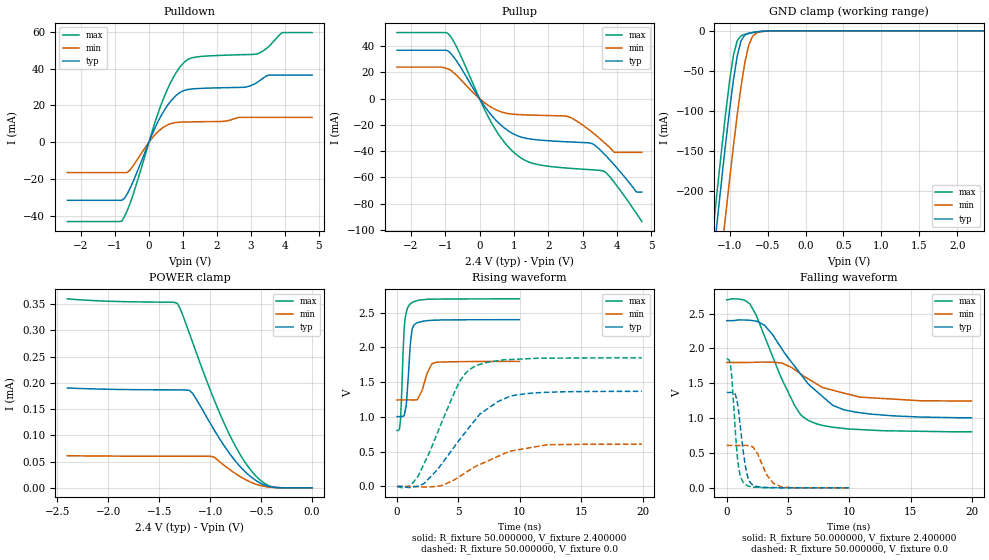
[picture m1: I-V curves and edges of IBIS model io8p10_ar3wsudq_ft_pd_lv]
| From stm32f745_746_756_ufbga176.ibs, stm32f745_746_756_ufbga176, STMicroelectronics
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|   Model io8p10_ar3wsudq_ft_pd_lv
[Model]  io8p10_ar3wsudq_ft_pd_lv
Model_type I/O
Polarity   Non-Inverting
Enable   Active-Low
Vinl =   0.720000V
Vinh =   1.680000V
Vmeas =  1.200000V
Cref =   40.000000pF
Rref =   100.000000M
Vref =   0.0V
C_comp   3.720900pF   3.684200pF   3.822900pF
[Temperature Range]   25.000000   0.125000k   -40.000000
[Pullup Reference]   2.400000V   1.800000V   2.700000V
[Pulldown Reference]   0.0V   0.0V   0.0V
[POWER Clamp Reference]   2.400000V   1.800000V   2.700000V
[GND Clamp Reference]   0.0V   0.0V   0.0V
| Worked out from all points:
|   slope of the pulldown table from 0 to 0.36 V, typ, clamps not added: 25 ohm
|   slope of the pullup table from 0 to 0.36 V, typ, clamps not added: 27.7 ohm
|   GND clamp passes 1 mA (typ) near -0.62 V on its own axis
|   rising waveform, R_fixture 50.000000, V_fixture 2.400000: 20-80 % time 334ps typ, 653ps min, 263ps max; typ from 1 V to 2.4 V
|   rising waveform, R_fixture 50.000000, V_fixture 0.0: 20-80 % time 3.76ns typ, 4ns min, 2.7ns max; typ from 0 V to 1.37 V
|   falling waveform, R_fixture 50.000000, V_fixture 2.400000: 20-80 % time 3.96ns typ, 4.04ns min, 2.77ns max; typ from 2.4 V to 1 V
|   falling waveform, R_fixture 50.000000, V_fixture 0.0: 20-80 % time 590ps typ, 1.03ns min, 462ps max; typ from 1.37 V to 0 V
[Pulldown]
|Voltage   I(typ)   I(min)   I(max)
-2.4V     -31.47mA   -16.45mA   -43.01mA
-800mV    -31.47mA   -16.45mA   -42.85mA
-480mV    -21.98mA   -13.17mA   -29.2mA
80mV      3.63mA     1.966mA    5.014mA
480mV     18.15mA    8.738mA    26.02mA
800mV     25.38mA    10.72mA    37.77mA
1.12V     28.53mA    11.02mA    44.6mA
2.8V      29.84mA    13.51mA    47.53mA
3.2V      32.66mA    13.51mA    48.04mA
3.52V     36.44mA    13.51mA    51.84mA
3.92V     36.44mA    13.51mA    59.49mA
4.8V      36.44mA    13.51mA    59.49mA
[Pullup]
|Voltage   I(typ)   I(min)   I(max)
-2.4V     36.91mA    24.03mA    50.36mA
-960mV    36.91mA    23.05mA    50.36mA
-640mV    27.65mA    17.04mA    37.98mA
320mV     -11.75mA   -6.207mA   -17.08mA
960mV     -26.47mA   -11.82mA   -40.02mA
1.52V     -30.88mA   -12.51mA   -49.05mA
2.56V     -32.88mA   -13.52mA   -52.9mA
3.28V     -34.25mA   -25.64mA   -54.18mA
3.6V      -41.44mA   -32.74mA   -55.03mA
3.92V     -50.46mA   -40.9mA    -63.79mA
4.56V     -71.1mA    -40.9mA    -87.27mA
4.72V     -71.1mA    -40.9mA    -93.6mA
[GND_clamp]
|Voltage   I(typ)   I(min)   I(max)
-2.4V     -1.429A    -1.514A    -1.399A
-1.25V    -315.9mA   -407.2mA   -278.2mA
-1.2V     -270.1mA   -361.3mA   -232.1mA
-1.15V    -225mA     -316mA     -186.8mA
-1.1V     -180.9mA   -271.3mA   -142.7mA
-1.05V    -138.2mA   -227.5mA   -100.5mA
-950mV    -61.14mA   -143.6mA   -30.44mA
-900mV    -31.24mA   -104.7mA   -12.15mA
-850mV    -12.5mA    -69.41mA   -6.236mA
-750mV    -2.91mA    -18.35mA   -3.195mA
-600mV    -761.5uA   -1.227mA   -751.9uA
2.35V     58.09uA    37.93uA    67.25uA
[POWER_clamp]
|Voltage   I(typ)   I(min)   I(max)
-2.4V     190.2uA    61.19uA    359.9uA
-1.32V    186.6uA    60.14uA    351.2uA
-1.29V    186.5uA    60.13uA    339.6uA
-1.2V     185.4uA    60.11uA    292.6uA
-1.17V    179.2uA    60.11uA    276.3uA
-960mV    110.2uA    58.62uA    167.5uA
-870mV    82.44uA    43.99uA    126.3uA
-750mV    50.58uA    26.92uA    78.64uA
-630mV    25.94uA    13.41uA    41.02uA
-510mV    9.22uA     4.527uA    14.97uA
-420mV    2.425uA    1.38uA     3.75uA
0V        0A         0A         0A
[Ramp]
| variable   typ   min   max
dV/dt_r  0.82140/3.76061n   0.36532/4.00428n   1.11270/2.70280n
dV/dt_f  0.83334/3.95761n   0.33270/4.10622n   1.13610/2.77089n
R_load = 50.000000
[Rising Waveform]
R_fixture= 50.000000
V_fixture= 2.400000
V_fixture_min= 1.800000
V_fixture_max= 2.700000
|time   V(typ)   V(min)   V(max)
0s        1.005V     1.245V     804.4mV
200.2ps   1.005V     1.245V     830mV
280.3ps   1.005V     1.245V     951.6mV
580.6ps   1.018V     1.246V     2.261V
760.8ps   1.192V     1.246V     2.509V
1.021ns   1.879V     1.245V     2.615V
1.241ns   2.27V      1.245V     2.645V
1.762ns   2.361V     1.285V     2.679V
2.863ns   2.391V     1.768V     2.694V
9.97ns    2.399V     1.799V     2.698V
[Rising Waveform]
R_fixture= 50.000000
V_fixture= 0.0
V_fixture_min= 0.0
V_fixture_max= 0.0
|time   V(typ)   V(min)   V(max)
0s        159.7uV    64.35uV    111.4uV
1.081ns   -14.22mV   123.7uV    11.6mV
1.682ns   3.873mV    -934.1uV   138.3mV
3.283ns   240mV      2.913mV    767.5mV
5.005ns   652.9mV    133.3mV    1.478V
6.286ns   939.9mV    277.9mV    1.722V
8.248ns   1.224V     434.7mV    1.81V
9.57ns    1.311V     518.9mV    1.829V
12.25ns   1.355V     600.4mV    1.845V
19.94ns   1.369V     608.4mV    1.85V
[Falling Waveform]
R_fixture= 50.000000
V_fixture= 2.400000
V_fixture_min= 1.800000
V_fixture_max= 2.700000
|time   V(typ)   V(min)   V(max)
0s        2.399V     1.799V     2.698V
1.401ns   2.408V     1.799V     2.697V
1.882ns   2.405V     1.8V       2.641V
3.083ns   2.332V     1.804V     2.174V
4.484ns   1.996V     1.792V     1.563V
5.526ns   1.746V     1.697V     1.183V
6.647ns   1.489V     1.563V     967.6mV
8.649ns   1.183V     1.401V     869.8mV
9.85ns    1.109V     1.346V     846.3mV
19.94ns   1.005V     1.245V     804.4mV
[Falling Waveform]
R_fixture= 50.000000
V_fixture= 0.0
V_fixture_min= 0.0
V_fixture_max= 0.0
|time   V(typ)   V(min)   V(max)
0s        1.369V     608.4mV    1.85V
320.3ps   1.369V     608.4mV    1.735V
820.8ps   1.27V      608.2mV    538.9mV
1.061ns   954.1mV    608mV      207.2mV
1.421ns   429.6mV    608.6mV    63.62mV
1.702ns   163mV      608mV      29.62mV
2.062ns   50.38mV    591.2mV    14.09mV
3.283ns   5.229mV    180.2mV    2.415mV
4.464ns   1.649mV    13.82mV    914uV
9.97ns    159.7uV    64.35uV    111.4uV
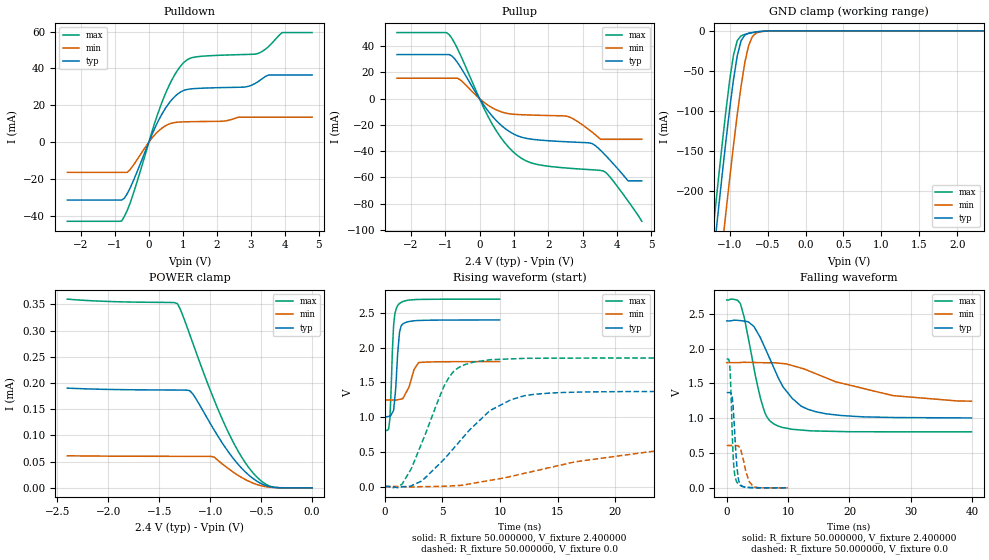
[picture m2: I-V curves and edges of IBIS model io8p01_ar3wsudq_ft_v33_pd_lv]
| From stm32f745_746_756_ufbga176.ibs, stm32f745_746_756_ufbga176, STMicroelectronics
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|   Model io8p01_ar3wsudq_ft_v33_pd_lv
[Model]  io8p01_ar3wsudq_ft_v33_pd_lv
Model_type I/O
Polarity   Non-Inverting
Enable   Active-Low
Vinl =   0.720000V
Vinh =   1.680000V
Vmeas =  1.200000V
Cref =   50.000000pF
Rref =   100.000000M
Vref =   0.0V
C_comp   3.737900pF   3.690400pF   3.817400pF
[Temperature Range]   25.000000   0.125000k   -40.000000
[Pullup Reference]   2.400000V   1.800000V   2.700000V
[Pulldown Reference]   0.0V   0.0V   0.0V
[POWER Clamp Reference]   2.400000V   1.800000V   2.700000V
[GND Clamp Reference]   0.0V   0.0V   0.0V
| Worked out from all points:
|   slope of the pulldown table from 0 to 0.36 V, typ, clamps not added: 25 ohm
|   slope of the pullup table from 0 to 0.36 V, typ, clamps not added: 27.7 ohm
|   GND clamp passes 1 mA (typ) near -0.62 V on its own axis
|   rising waveform, R_fixture 50.000000, V_fixture 2.400000: 20-80 % time 349ps typ, 698ps min, 272ps max; typ from 1 V to 2.4 V
|   rising waveform, R_fixture 50.000000, V_fixture 0.0: 20-80 % time 4.73ns typ, 12.1ns min, 2.67ns max; typ from 0 V to 1.37 V
|   falling waveform, R_fixture 50.000000, V_fixture 2.400000: 20-80 % time 5.02ns typ, 12.5ns min, 2.7ns max; typ from 2.4 V to 1 V
|   falling waveform, R_fixture 50.000000, V_fixture 0.0: 20-80 % time 599ps typ, 1.08ns min, 461ps max; typ from 1.37 V to 0 V
[Pulldown]
|Voltage   I(typ)   I(min)   I(max)
-2.4V     -31.47mA   -16.45mA   -43.01mA
-800mV    -31.47mA   -16.45mA   -42.85mA
-480mV    -21.98mA   -13.17mA   -29.2mA
80mV      3.63mA     1.966mA    5.014mA
480mV     18.15mA    8.738mA    26.02mA
800mV     25.38mA    10.72mA    37.77mA
1.12V     28.53mA    11.02mA    44.6mA
2.8V      29.84mA    13.49mA    47.53mA
3.2V      32.65mA    13.49mA    48.04mA
3.52V     36.4mA     13.49mA    51.82mA
3.92V     36.4mA     13.49mA    59.44mA
4.8V      36.4mA     13.49mA    59.44mA
[Pullup]
|Voltage   I(typ)   I(min)   I(max)
-2.4V     33.56mA    15.57mA    50.33mA
-960mV    33.56mA    15.57mA    50.33mA
-800mV    32.44mA    15.57mA    45.78mA
-560mV    24.28mA    14.31mA    33.53mA
320mV     -11.75mA   -6.207mA   -17.08mA
960mV     -26.47mA   -11.82mA   -40.02mA
1.52V     -30.88mA   -12.51mA   -49.05mA
2.56V     -32.88mA   -13.52mA   -52.9mA
3.28V     -34.25mA   -25.62mA   -54.18mA
3.6V      -41.44mA   -30.96mA   -55.03mA
4.32V     -62.58mA   -30.96mA   -77.98mA
4.72V     -62.58mA   -30.96mA   -93.4mA
[GND_clamp]
|Voltage   I(typ)   I(min)   I(max)
-2.4V     -1.437A    -1.518A    -1.41A
-1.25V    -315.9mA   -407.2mA   -278.2mA
-1.2V     -270.1mA   -361.3mA   -232.1mA
-1.15V    -225mA     -316mA     -186.8mA
-1.1V     -180.9mA   -271.3mA   -142.7mA
-1.05V    -138.2mA   -227.5mA   -100.5mA
-950mV    -61.14mA   -143.6mA   -30.44mA
-900mV    -31.24mA   -104.7mA   -12.15mA
-850mV    -12.5mA    -69.41mA   -6.236mA
-750mV    -2.91mA    -18.35mA   -3.195mA
-600mV    -761.5uA   -1.227mA   -751.9uA
2.35V     58.09uA    37.93uA    67.25uA
[POWER_clamp]
|Voltage   I(typ)   I(min)   I(max)
-2.4V     190.2uA    61.19uA    359.9uA
-1.32V    186.6uA    60.14uA    351.2uA
-1.29V    186.5uA    60.13uA    339.6uA
-1.2V     185.4uA    60.11uA    292.6uA
-1.17V    179.2uA    60.11uA    276.3uA
-960mV    110.2uA    58.62uA    167.5uA
-870mV    82.44uA    43.99uA    126.3uA
-750mV    50.58uA    26.92uA    78.64uA
-630mV    25.94uA    13.41uA    41.02uA
-510mV    9.22uA     4.527uA    14.97uA
-420mV    2.425uA    1.38uA     3.75uA
0V        0A         0A         0A
[Ramp]
| variable   typ   min   max
dV/dt_r  0.82158/4.72959n   0.38163/12.88267n   1.11054/2.67180n
dV/dt_f  0.83682/5.02733n   0.32214/12.54954n   1.13792/2.70520n
R_load = 50.000000
[Rising Waveform]
R_fixture= 50.000000
V_fixture= 2.400000
V_fixture_min= 1.800000
V_fixture_max= 2.700000
|time   V(typ)   V(min)   V(max)
0s        1.005V     1.245V     804.5mV
320.3ps   1.009V     1.245V     821.1mV
440.4ps   1.014V     1.245V     967.3mV
660.7ps   1.065V     1.245V     1.956V
760.8ps   1.094V     1.245V     2.303V
961ps     1.441V     1.245V     2.541V
1.201ns   2.073V     1.252V     2.624V
1.441ns   2.32V      1.261V     2.654V
2.943ns   2.391V     1.786V     2.695V
9.97ns    2.399V     1.799V     2.699V
[Rising Waveform]
R_fixture= 50.000000
V_fixture= 0.0
V_fixture_min= 0.0
V_fixture_max= 0.0
|time   V(typ)   V(min)   V(max)
0s        87.36uV    36.22uV    196.7uV
1.522ns   -4.899mV   -560.6uV   38.31mV
3.283ns   88.55mV    -884.9uV   656.5mV
5.526ns   463.4mV    6.763mV    1.557V
6.326ns   616.6mV    13.38mV    1.703V
7.688ns   865.9mV    46.6mV     1.791V
10.89ns   1.244V     143.3mV    1.838V
13.21ns   1.331V     230.7mV    1.847V
25.23ns   1.368V     550.7mV    1.85V
39.88ns   1.369V     608.5mV    1.85V
[Falling Waveform]
R_fixture= 50.000000
V_fixture= 2.400000
V_fixture_min= 1.800000
V_fixture_max= 2.700000
|time   V(typ)   V(min)   V(max)
0s        2.399V     1.799V     2.699V
2.242ns   2.402V     1.801V     2.642V
4.404ns   2.32V      1.802V     1.734V
5.526ns   2.149V     1.799V     1.278V
6.486ns   1.961V     1.798V     1.029V
7.848ns   1.69V      1.797V     909.8mV
10.65ns   1.288V     1.757V     841.6mV
14.57ns   1.092V     1.638V     817.2mV
27.07ns   1.011V     1.326V     805.4mV
39.88ns   1.005V     1.245V     804.5mV
[Falling Waveform]
R_fixture= 50.000000
V_fixture= 0.0
V_fixture_min= 0.0
V_fixture_max= 0.0
|time   V(typ)   V(min)   V(max)
0s        1.369V     608.5mV    1.85V
460.5ps   1.37V      608.4mV    1.795V
660.7ps   1.366V     608.3mV    1.448V
860.9ps   1.327V     608.1mV    891.7mV
1.161ns   1.004V     607.9mV    300mV
1.602ns   374.7mV    607.9mV    91.22mV
2.222ns   47.23mV    567.1mV    34.18mV
3.143ns   9.028mV    223.5mV    10.92mV
4.364ns   3.143mV    13.36mV    3.352mV
9.97ns    87.36uV    36.22uV    196.7uV
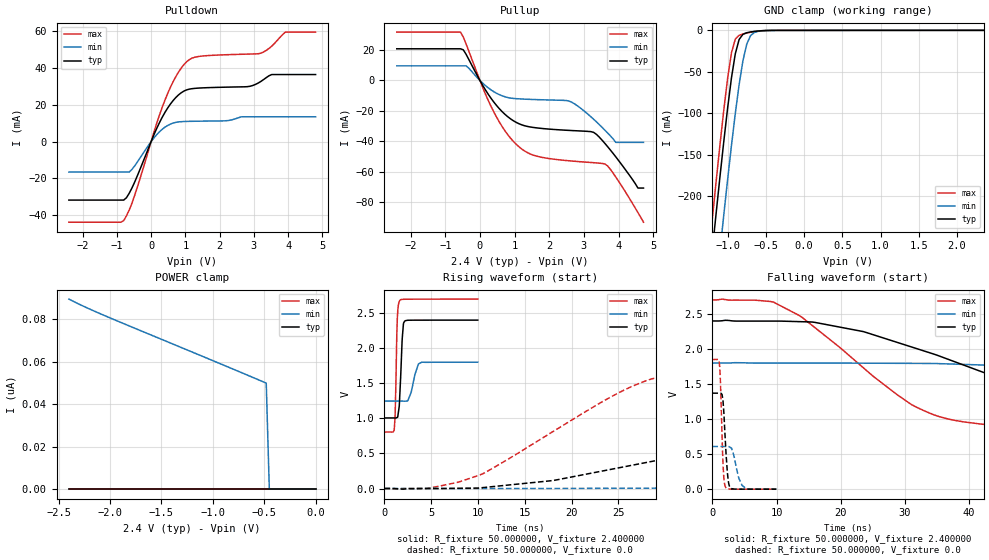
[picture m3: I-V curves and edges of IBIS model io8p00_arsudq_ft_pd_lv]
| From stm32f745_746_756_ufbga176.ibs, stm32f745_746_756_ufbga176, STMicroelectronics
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|   Model io8p00_arsudq_ft_pd_lv
[Model]  io8p00_arsudq_ft_pd_lv
Model_type I/O
Polarity   Non-Inverting
Enable   Active-Low
Vinl =   0.720000V
Vinh =   1.680000V
Vmeas =  1.200000V
Cref =   50.000000pF
Rref =   100.000000M
Vref =   0.0V
C_comp   2.238800pF   2.178700pF   2.334000pF
[Temperature Range]   25.000000   0.125000k   -40.000000
[Pullup Reference]   2.400000V   1.800000V   2.700000V
[Pulldown Reference]   0.0V   0.0V   0.0V
[POWER Clamp Reference]   2.400000V   1.800000V   2.700000V
[GND Clamp Reference]   0.0V   0.0V   0.0V
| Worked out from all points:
|   slope of the pulldown table from 0 to 0.36 V, typ, clamps not added: 25 ohm
|   slope of the pullup table from 0 to 0.36 V, typ, clamps not added: 27.7 ohm
|   GND clamp passes 1 mA (typ) near -0.62 V on its own axis
|   rising waveform, R_fixture 50.000000, V_fixture 2.400000: 20-80 % time 271ps typ, 604ps min, 182ps max; typ from 1 V to 2.4 V
|   rising waveform, R_fixture 50.000000, V_fixture 0.0: 20-80 % time 32.8ns typ, 82.1ns min, 14.3ns max; typ from 0 V to 1.37 V
|   falling waveform, R_fixture 50.000000, V_fixture 2.400000: 20-80 % time 29.4ns typ, 74.2ns min, 15.7ns max; typ from 2.4 V to 1 V
|   falling waveform, R_fixture 50.000000, V_fixture 0.0: 20-80 % time 522ps typ, 975ps min, 384ps max; typ from 1.37 V to 0 V
[Pulldown]
|Voltage   I(typ)   I(min)   I(max)
-2.4V     -31.73mA   -16.51mA   -43.74mA
-800mV    -31.73mA   -16.51mA   -42.87mA
-480mV    -21.98mA   -13.17mA   -29.2mA
80mV      3.63mA     1.966mA    5.014mA
480mV     18.15mA    8.738mA    26.02mA
800mV     25.38mA    10.72mA    37.77mA
1.12V     28.53mA    11.02mA    44.6mA
2.8V      29.84mA    13.49mA    47.53mA
3.2V      32.65mA    13.49mA    48.04mA
3.52V     36.42mA    13.49mA    51.83mA
3.92V     36.42mA    13.49mA    59.49mA
4.8V      36.42mA    13.49mA    59.49mA
[Pullup]
|Voltage   I(typ)   I(min)   I(max)
-2.4V     20.89mA    9.659mA    31.9mA
-560mV    20.89mA    9.659mA    31.9mA
-400mV    17.28mA    9.659mA    24.07mA
320mV     -11.75mA   -6.207mA   -17.08mA
960mV     -26.47mA   -11.82mA   -40.02mA
1.52V     -30.88mA   -12.51mA   -49.05mA
2.56V     -32.88mA   -13.48mA   -52.9mA
3.28V     -34.19mA   -25.52mA   -54.18mA
3.6V      -41.31mA   -32.62mA   -54.97mA
3.92V     -50.32mA   -40.8mA    -63.63mA
4.56V     -70.9mA    -40.8mA    -87.08mA
4.72V     -70.9mA    -40.8mA    -93.4mA
[GND_clamp]
|Voltage   I(typ)   I(min)   I(max)
-2.4V     -1.424A    -1.508A    -1.393A
-1.25V    -311.2mA   -401.9mA   -273.3mA
-1.2V     -265.4mA   -356.1mA   -227.2mA
-1.15V    -220.4mA   -310.8mA   -181.9mA
-1.1V     -176.3mA   -266.2mA   -137.9mA
-1.05V    -133.8mA   -222.5mA   -95.87mA
-950mV    -57.3mA    -138.9mA   -26.99mA
-900mV    -28.28mA   -100.4mA   -10.6mA
-850mV    -11.02mA   -65.54mA   -5.972mA
-750mV    -2.846mA   -16.51mA   -3.192mA
-600mV    -761.3uA   -1.173mA   -751.9uA
2.35V     58.09uA    37.92uA    67.25uA
[POWER_clamp]
|Voltage   I(typ)   I(min)   I(max)
-2.4V     0A         89.62nA    0A
-2.04V    0A         81.57nA    0A
-480mV    0A         50.01nA    0A
-450mV    0A         0A         0A
0V        0A         0A         0A
[Ramp]
| variable   typ   min   max
dV/dt_r  0.82170/32.82366n   0.36242/85.09830n   1.11018/14.28854n
dV/dt_f  0.83712/29.36745n   0.32760/79.42308n   1.13746/15.74331n
R_load = 50.000000
[Rising Waveform]
R_fixture= 50.000000
V_fixture= 2.400000
V_fixture_min= 1.800000
V_fixture_max= 2.700000
|time   V(typ)   V(min)   V(max)
0s        1.005V     1.245V     804.1mV
1.041ns   1.005V     1.245V     831.1mV
1.141ns   1.005V     1.246V     1.042V
1.381ns   1.014V     1.246V     2.441V
1.642ns   1.336V     1.246V     2.679V
1.902ns   2.139V     1.245V     2.694V
2.162ns   2.384V     1.244V     2.696V
2.843ns   2.398V     1.366V     2.697V
3.644ns   2.398V     1.776V     2.698V
9.97ns    2.399V     1.799V     2.699V
[Rising Waveform]
R_fixture= 50.000000
V_fixture= 0.0
V_fixture_min= 0.0
V_fixture_max= 0.0
|time   V(typ)   V(min)   V(max)
0s        4.156nV    252.6nV    1.585nV
5.005ns   -211uV     -65.32uV   10.99mV
10.51ns   12.92mV    -64.87uV   210.4mV
23.52ns   255.6mV    2.731mV    1.256V
28.03ns   372.2mV    4.599mV    1.539V
39.04ns   686.9mV    30.21mV    1.765V
58.06ns   1.115V     86.32mV    1.831V
78.08ns   1.31V      184.3mV    1.849V
148.1ns   1.367V     489.6mV    1.851V
249.2ns   1.369V     608.5mV    1.851V
[Falling Waveform]
R_fixture= 50.000000
V_fixture= 2.400000
V_fixture_min= 1.800000
V_fixture_max= 2.700000
|time   V(typ)   V(min)   V(max)
0s        2.399V     1.799V     2.699V
9.51ns    2.397V     1.798V     2.668V
16.02ns   2.378V     1.798V     2.301V
31.03ns   2.028V     1.794V     1.206V
35.54ns   1.893V     1.79V      1.03V
42.04ns   1.672V     1.771V     926.7mV
57.56ns   1.278V     1.723V     851.2mV
88.09ns   1.069V     1.553V     815.1mV
124.6ns   1.024V     1.381V     805.3mV
249.2ns   1.005V     1.245V     804.1mV
[Falling Waveform]
R_fixture= 50.000000
V_fixture= 0.0
V_fixture_min= 0.0
V_fixture_max= 0.0
|time   V(typ)   V(min)   V(max)
0s        1.369V     608.5mV    1.851V
1.061ns   1.369V     608.4mV    1.818V
1.241ns   1.369V     608.4mV    1.571V
1.682ns   1.232V     608.2mV    321.7mV
1.842ns   1.003V     607.9mV    112.1mV
2.042ns   655.1mV    607.8mV    32.3mV
2.482ns   117.3mV    610.1mV    2.554mV
2.843ns   16.84mV    593.5mV    356.4uV
4.645ns   56.98uV    52.38mV    25.4uV
9.97ns    4.156nV    252.6nV    1.585nV
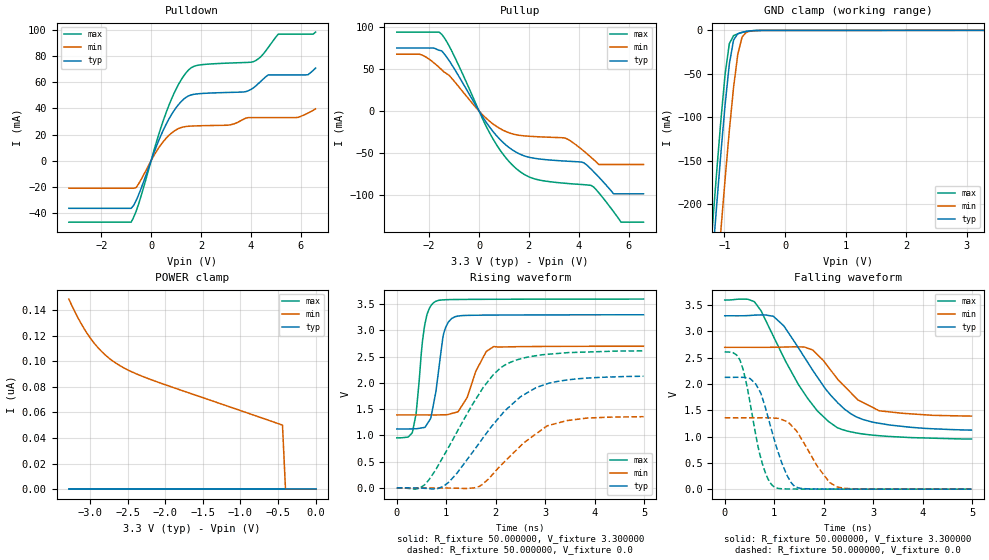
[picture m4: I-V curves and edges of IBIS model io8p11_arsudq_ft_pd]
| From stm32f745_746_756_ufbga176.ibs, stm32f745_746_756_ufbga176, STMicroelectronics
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|   Model io8p11_arsudq_ft_pd
[Model]  io8p11_arsudq_ft_pd
Model_type I/O
Polarity   Non-Inverting
Enable   Active-Low
Vinl =   0.990000V
Vinh =   2.310000V
Vmeas =  1.650000V
Cref =   30.000000pF
Rref =   100.000000M
Vref =   0.0V
C_comp   2.292100pF   2.228000pF   2.366600pF
[Temperature Range]   25.000000   0.125000k   -40.000000
[Pullup Reference]   3.300000V   2.700000V   3.600000V
[Pulldown Reference]   0.0V   0.0V   0.0V
[POWER Clamp Reference]   3.300000V   2.700000V   3.600000V
[GND Clamp Reference]   0.0V   0.0V   0.0V
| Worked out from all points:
|   slope of the pulldown table from 0 to 0.495 V, typ, clamps not added: 20.9 ohm
|   slope of the pullup table from 0 to 0.495 V, typ, clamps not added: 22.6 ohm
|   GND clamp passes 1 mA (typ) near -0.62 V on its own axis
|   rising waveform, R_fixture 50.000000, V_fixture 3.300000: 20-80 % time 197ps typ, 342ps min, 161ps max; typ from 1.12 V to 3.3 V
|   rising waveform, R_fixture 50.000000, V_fixture 0.0: 20-80 % time 1.13ns typ, 947ps min, 998ps max; typ from 0 V to 2.13 V
|   falling waveform, R_fixture 50.000000, V_fixture 3.300000: 20-80 % time 1.01ns typ, 785ps min, 978ps max; typ from 3.3 V to 1.12 V
|   falling waveform, R_fixture 50.000000, V_fixture 0.0: 20-80 % time 414ps typ, 535ps min, 331ps max; typ from 2.13 V to 0 V
[Pulldown]
|Voltage   I(typ)   I(min)   I(max)
-3.3V     -36.46mA   -21.1mA    -47.09mA
-800mV    -36.46mA   -21.1mA    -47.09mA
-600mV    -30.5mA    -20.54mA   -38.69mA
700mV     31.4mA     19.11mA    41.71mA
1.2V      45.15mA    25.37mA    61.75mA
1.6V      50.35mA    26.5mA     71.06mA
3.1V      52.27mA    27.26mA    74.75mA
4.1V      55.7mA     32.99mA    75.8mA
4.7V      65.72mA    32.99mA    86.69mA
5.1V      65.72mA    32.99mA    96.9mA
6.3V      65.87mA    36.5mA     96.9mA
6.6V      70.93mA    39.71mA    98.5mA
[Pullup]
|Voltage   I(typ)   I(min)   I(max)
-3.3V     74.73mA    67.41mA    93.65mA
-2.3V     74.73mA    66.57mA    93.65mA
-1.5V     71.37mA    49.01mA    91.08mA
500mV     -22.07mA   -14mA      -30.03mA
1.6V      -50.64mA   -28.81mA   -70.96mA
3.5V      -59.53mA   -32.65mA   -85.92mA
4.2V      -61.43mA   -47.48mA   -87.46mA
4.5V      -69.06mA   -55.13mA   -88.38mA
4.8V      -78.23mA   -63.5mA    -96.84mA
5.4V      -98.3mA    -63.5mA    -119.6mA
5.7V      -98.3mA    -63.5mA    -132mA
6.6V      -98.3mA    -63.5mA    -132mA
[GND_clamp]
|Voltage   I(typ)   I(min)   I(max)
-3.3V     -2.315A    -2.395A    -2.287A
-1.2V     -265.5mA   -356.1mA   -227.2mA
-1.13V    -202.7mA   -292.9mA   -164.1mA
-1.06V    -142.2mA   -231.2mA   -104.1mA
-990mV    -85.98mA   -171.6mA   -50.73mA
-920mV    -38.81mA   -115.5mA   -15.29mA
-850mV    -11.09mA   -65.61mA   -6.016mA
-780mV    -3.793mA   -27.42mA   -3.89mA
-710mV    -2.098mA   -7.698mA   -2.396mA
-640mV    -1.159mA   -2.127mA   -1.234mA
-570mV    -535.1uA   -807.4uA   -490.2uA
3.28V     81.28uA    57.87uA    93.98uA
[POWER_clamp]
|Voltage   I(typ)   I(min)   I(max)
-3.28V    0A         148.5nA    0A
-3.2V     0A         138.6nA    0A
-3.12V    0A         129.7nA    0A
-3.04V    0A         122nA      0A
-2.96V    0A         115.3nA    0A
-2.8V     0A         105.1nA    0A
-2.6V     0A         96.44nA    0A
-2.4V     0A         90.52nA    0A
-2.16V    0A         84.97nA    0A
-440mV    0A         50.04nA    0A
-400mV    0A         0A         0A
0V        0A         0A         0A
[Ramp]
| variable   typ   min   max
dV/dt_r  1.26078/1.11589n   0.80526/0.93834n   1.55994/0.99620n
dV/dt_f  1.27656/0.99515n   0.77106/0.76088n   1.56956/0.97105n
R_load = 50.000000
[Rising Waveform]
R_fixture= 50.000000
V_fixture= 3.300000
V_fixture_min= 2.700000
V_fixture_max= 3.600000
|time   V(typ)   V(min)   V(max)
0s        1.123V     1.391V     953.9mV
320.3ps   1.126V     1.391V     1.078V
390.4ps   1.127V     1.391V     1.413V
560.6ps   1.152V     1.391V     3.084V
690.7ps   1.344V     1.39V      3.472V
780.8ps   1.787V     1.39V      3.552V
951ps     2.952V     1.393V     3.584V
1.171ns   3.259V     1.434V     3.589V
1.962ns   3.293V     2.694V     3.594V
4.985ns   3.299V     2.699V     3.598V
[Rising Waveform]
R_fixture= 50.000000
V_fixture= 0.0
V_fixture_min= 0.0
V_fixture_max= 0.0
|time   V(typ)   V(min)   V(max)
0s        345.8uV    197uV      652uV
470.5ps   -2.822mV   136.3uV    -123uV
650.7ps   -14.07mV   197.3uV    155.3mV
951ps     37.14mV    -1.041mV   616.5mV
1.662ns   848mV      26.7mV     1.787V
2.182ns   1.469V     504.1mV    2.341V
2.503ns   1.738V     801.3mV    2.46V
3.043ns   1.985V     1.184V     2.545V
3.854ns   2.093V     1.332V     2.589V
4.985ns   2.127V     1.357V     2.611V
[Falling Waveform]
R_fixture= 50.000000
V_fixture= 3.300000
V_fixture_min= 2.700000
V_fixture_max= 3.600000
|time   V(typ)   V(min)   V(max)
0s        3.299V     2.699V     3.598V
600.6ps   3.311V     2.699V     3.565V
740.7ps   3.314V     2.699V     3.382V
991ps     3.282V     2.7V       2.894V
1.201ns   3.098V     2.704V     2.489V
1.772ns   2.272V     2.65V      1.611V
2.272ns   1.656V     2.103V     1.171V
2.693ns   1.363V     1.698V     1.065V
3.123ns   1.253V     1.491V     1.017V
4.985ns   1.123V     1.391V     953.9mV
[Falling Waveform]
R_fixture= 50.000000
V_fixture= 0.0
V_fixture_min= 0.0
V_fixture_max= 0.0
|time   V(typ)   V(min)   V(max)
0s        2.127V     1.357V     2.611V
310.3ps   2.128V     1.357V     2.452V
450.5ps   2.117V     1.357V     1.959V
720.7ps   1.843V     1.358V     624.7mV
870.9ps   1.385V     1.358V     203.6mV
1.011ns   912.7mV    1.351V     38.3mV
1.391ns   72.48mV    1.167V     2.895mV
1.872ns   3.192mV    434.6mV    1.884mV
2.282ns   1.722mV    39.35mV    1.565mV
4.985ns   345.8uV    197uV      652uV
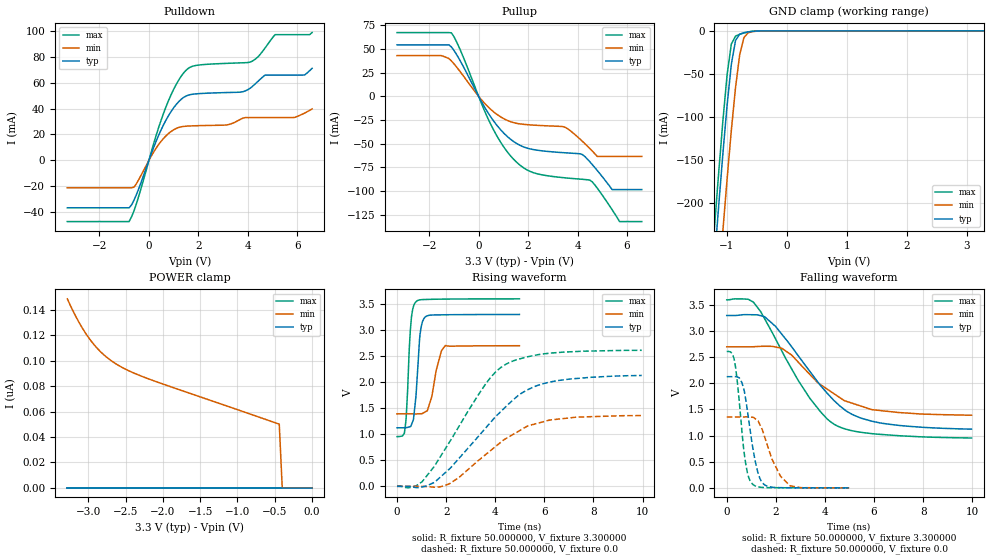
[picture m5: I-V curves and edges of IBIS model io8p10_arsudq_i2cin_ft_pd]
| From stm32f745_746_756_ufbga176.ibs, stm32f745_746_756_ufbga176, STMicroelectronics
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|   Model io8p10_arsudq_i2cin_ft_pd
[Model]  io8p10_arsudq_i2cin_ft_pd
Model_type I/O
Polarity   Non-Inverting
Enable   Active-Low
Vinl =   0.990000V
Vinh =   2.310000V
Vmeas =  1.650000V
Cref =   40.000000pF
Rref =   100.000000M
Vref =   0.0V
C_comp   2.280000pF   2.217100pF   2.355700pF
[Temperature Range]   25.000000   0.125000k   -40.000000
[Pullup Reference]   3.300000V   2.700000V   3.600000V
[Pulldown Reference]   0.0V   0.0V   0.0V
[POWER Clamp Reference]   3.300000V   2.700000V   3.600000V
[GND Clamp Reference]   0.0V   0.0V   0.0V
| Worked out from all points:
|   slope of the pulldown table from 0 to 0.495 V, typ, clamps not added: 20.9 ohm
|   slope of the pullup table from 0 to 0.495 V, typ, clamps not added: 22.6 ohm
|   GND clamp passes 1 mA (typ) near -0.62 V on its own axis
|   rising waveform, R_fixture 50.000000, V_fixture 3.300000: 20-80 % time 194ps typ, 346ps min, 164ps max; typ from 1.12 V to 3.3 V
|   rising waveform, R_fixture 50.000000, V_fixture 0.0: 20-80 % time 2.52ns typ, 2.28ns min, 2.11ns max; typ from 0 V to 2.13 V
|   falling waveform, R_fixture 50.000000, V_fixture 3.300000: 20-80 % time 2.25ns typ, 2.05ns min, 2.04ns max; typ from 3.3 V to 1.12 V
|   falling waveform, R_fixture 50.000000, V_fixture 0.0: 20-80 % time 433ps typ, 668ps min, 339ps max; typ from 2.13 V to 0 V
[Pulldown]
|Voltage   I(typ)   I(min)   I(max)
-3.3V     -36.46mA   -21.1mA    -47.09mA
-800mV    -36.46mA   -21.1mA    -47.09mA
-600mV    -30.5mA    -20.54mA   -38.69mA
700mV     31.4mA     19.11mA    41.71mA
1.2V      45.15mA    25.37mA    61.75mA
1.6V      50.35mA    26.5mA     71.06mA
3.1V      52.27mA    27.26mA    74.75mA
4.1V      55.7mA     32.99mA    75.8mA
4.7V      65.72mA    32.99mA    86.69mA
5.1V      65.72mA    32.99mA    96.9mA
6.3V      65.87mA    36.5mA     96.9mA
6.6V      70.93mA    39.71mA    98.5mA
[Pullup]
|Voltage   I(typ)   I(min)   I(max)
-3.3V     54.22mA    42.91mA    67.18mA
-1.1V     51.99mA    37.29mA    66.9mA
500mV     -22.07mA   -14mA      -30.03mA
1.5V      -49.1mA    -28.3mA    -68.56mA
2.2V      -56.04mA   -30.32mA   -80.35mA
3.5V      -59.53mA   -32.65mA   -85.92mA
4.2V      -61.43mA   -47.49mA   -87.46mA
4.5V      -69.06mA   -55.12mA   -88.38mA
4.8V      -78.23mA   -63.4mA    -96.84mA
5.4V      -98.3mA    -63.4mA    -119.6mA
5.7V      -98.3mA    -63.4mA    -132mA
6.6V      -98.3mA    -63.4mA    -132mA
[GND_clamp]
|Voltage   I(typ)   I(min)   I(max)
-3.3V     -2.317A    -2.396A    -2.289A
-1.2V     -265.5mA   -356.1mA   -227.2mA
-1.13V    -202.7mA   -292.9mA   -164.1mA
-1.06V    -142.2mA   -231.2mA   -104.1mA
-990mV    -85.98mA   -171.6mA   -50.73mA
-920mV    -38.81mA   -115.5mA   -15.29mA
-850mV    -11.09mA   -65.61mA   -6.016mA
-780mV    -3.793mA   -27.42mA   -3.89mA
-710mV    -2.098mA   -7.698mA   -2.396mA
-640mV    -1.159mA   -2.127mA   -1.234mA
-570mV    -535.1uA   -807.4uA   -490.2uA
3.28V     81.28uA    57.87uA    93.98uA
[POWER_clamp]
|Voltage   I(typ)   I(min)   I(max)
-3.28V    0A         148.5nA    0A
-3.2V     0A         138.6nA    0A
-3.12V    0A         129.7nA    0A
-3.04V    0A         122nA      0A
-2.96V    0A         115.3nA    0A
-2.8V     0A         105.1nA    0A
-2.6V     0A         96.44nA    0A
-2.4V     0A         90.52nA    0A
-2.16V    0A         84.97nA    0A
-440mV    0A         50.04nA    0A
-400mV    0A         0A         0A
0V        0A         0A         0A
[Ramp]
| variable   typ   min   max
dV/dt_r  1.26654/2.50778n   0.81120/2.28797n   1.56312/2.10838n
dV/dt_f  1.28280/2.23992n   0.77730/2.03639n   1.57441/2.02897n
R_load = 50.000000
[Rising Waveform]
R_fixture= 50.000000
V_fixture= 3.300000
V_fixture_min= 2.700000
V_fixture_max= 3.600000
|time   V(typ)   V(min)   V(max)
0s        1.123V     1.391V     954mV
300.3ps   1.125V     1.391V     1.022V
370.4ps   1.127V     1.391V     1.295V
540.5ps   1.146V     1.391V     2.986V
670.7ps   1.286V     1.39V      3.453V
760.8ps   1.683V     1.39V      3.537V
940.9ps   2.928V     1.393V     3.579V
1.171ns   3.259V     1.434V     3.586V
1.972ns   3.293V     2.704V     3.593V
4.985ns   3.299V     2.699V     3.598V
[Rising Waveform]
R_fixture= 50.000000
V_fixture= 0.0
V_fixture_min= 0.0
V_fixture_max= 0.0
|time   V(typ)   V(min)   V(max)
0s        344.4uV    197.3uV    669.9uV
460.5ps   -2.521mV   135uV      -29.37mV
1.021ns   -11.67mV   -1.704mV   87.93mV
1.522ns   76.04mV    -17.07mV   385.3mV
2.142ns   336mV      50.68mV    853.3mV
3.644ns   1.137V     622mV      1.988V
4.444ns   1.534V     919.1mV    2.346V
5.265ns   1.841V     1.144V     2.48V
6.186ns   1.997V     1.268V     2.553V
9.97ns    2.127V     1.357V     2.611V
[Falling Waveform]
R_fixture= 50.000000
V_fixture= 3.300000
V_fixture_min= 2.700000
V_fixture_max= 3.600000
|time   V(typ)   V(min)   V(max)
0s        3.299V     2.699V     3.598V
880.9ps   3.314V     2.699V     3.608V
1.101ns   3.312V     2.701V     3.546V
1.542ns   3.275V     2.709V     3.237V
2.242ns   2.941V     2.671V     2.621V
3.383ns   2.23V      2.172V     1.715V
4.404ns   1.656V     1.791V     1.209V
5.125ns   1.401V     1.617V     1.091V
6.186ns   1.248V     1.483V     1.026V
9.97ns    1.123V     1.391V     954mV
[Falling Waveform]
R_fixture= 50.000000
V_fixture= 0.0
V_fixture_min= 0.0
V_fixture_max= 0.0
|time   V(typ)   V(min)   V(max)
0s        2.127V     1.357V     2.611V
300.3ps   2.129V     1.357V     2.469V
450.5ps   2.118V     1.357V     1.948V
620.6ps   2.011V     1.357V     1.074V
840.8ps   1.48V      1.359V     291.2mV
1.041ns   822.2mV    1.351V     77mV
1.451ns   99.43mV    1.11V      8.306mV
1.852ns   12.52mV    539.9mV    3.365mV
2.573ns   1.853mV    40.63mV    1.74mV
4.985ns   344.4uV    197.3uV    669.9uV
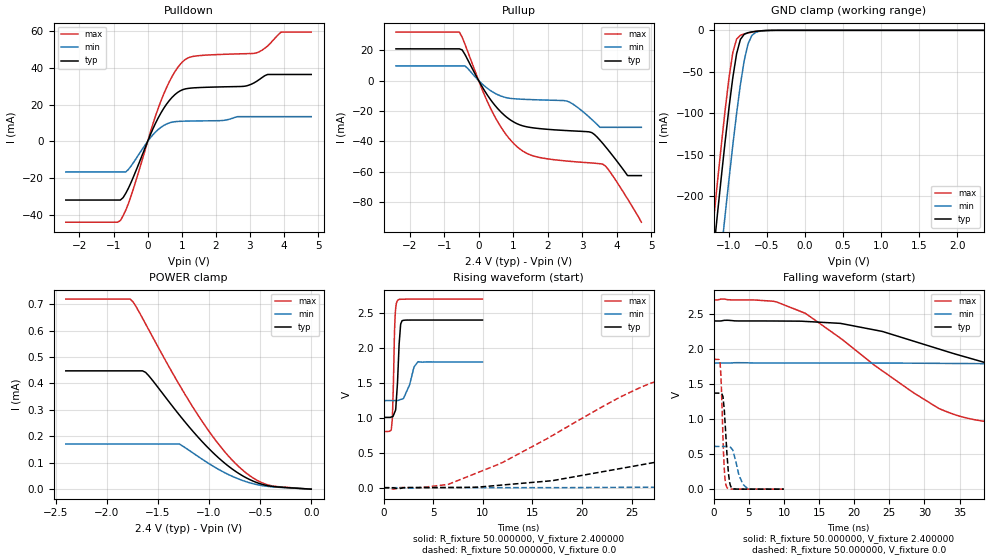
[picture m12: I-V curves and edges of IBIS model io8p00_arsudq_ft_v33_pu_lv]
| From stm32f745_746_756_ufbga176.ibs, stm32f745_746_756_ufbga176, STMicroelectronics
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|   Model io8p00_arsudq_ft_v33_pu_lv
[Model]  io8p00_arsudq_ft_v33_pu_lv
Model_type I/O
Polarity   Non-Inverting
Enable   Active-Low
Vinl =   0.720000V
Vinh =   1.680000V
Vmeas =  1.200000V
Cref =   50.000000pF
Rref =   100.000000M
Vref =   0.0V
C_comp   2.238700pF   2.180600pF   2.332300pF
[Temperature Range]   25.000000   0.125000k   -40.000000
[Pullup Reference]   2.400000V   1.800000V   2.700000V
[Pulldown Reference]   0.0V   0.0V   0.0V
[POWER Clamp Reference]   2.400000V   1.800000V   2.700000V
[GND Clamp Reference]   0.0V   0.0V   0.0V
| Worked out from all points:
|   slope of the pulldown table from 0 to 0.36 V, typ, clamps not added: 25 ohm
|   slope of the pullup table from 0 to 0.36 V, typ, clamps not added: 27.7 ohm
|   GND clamp passes 1 mA (typ) near -0.62 V on its own axis
|   rising waveform, R_fixture 50.000000, V_fixture 2.400000: 20-80 % time 301ps typ, 741ps min, 197ps max; typ from 1.01 V to 2.4 V
|   rising waveform, R_fixture 50.000000, V_fixture 0.0: 20-80 % time 31ns typ, 81.8ns min, 14.6ns max; typ from 0.001 V to 1.37 V
|   falling waveform, R_fixture 50.000000, V_fixture 2.400000: 20-80 % time 30ns typ, 81.9ns min, 15.8ns max; typ from 2.4 V to 1.01 V
|   falling waveform, R_fixture 50.000000, V_fixture 0.0: 20-80 % time 533ps typ, 1.03ns min, 386ps max; typ from 1.37 V to 0.001 V
[Pulldown]
|Voltage   I(typ)   I(min)   I(max)
-2.4V     -31.73mA   -16.51mA   -43.74mA
-800mV    -31.73mA   -16.51mA   -42.87mA
-480mV    -21.98mA   -13.17mA   -29.21mA
80mV      3.63mA     1.966mA    5.014mA
480mV     18.16mA    8.738mA    26.02mA
800mV     25.38mA    10.72mA    37.77mA
1.12V     28.53mA    11.02mA    44.6mA
2.8V      29.84mA    13.45mA    47.53mA
3.2V      32.59mA    13.45mA    48.03mA
3.52V     36.3mA     13.45mA    51.74mA
3.92V     36.3mA     13.45mA    59.27mA
4.8V      36.3mA     13.45mA    59.27mA
[Pullup]
|Voltage   I(typ)   I(min)   I(max)
-2.4V     20.87mA    9.659mA    31.88mA
-560mV    20.87mA    9.659mA    31.88mA
-400mV    17.27mA    9.659mA    24.06mA
320mV     -11.75mA   -6.207mA   -17.08mA
640mV     -20.52mA   -10.1mA    -30.35mA
960mV     -26.47mA   -11.82mA   -40.02mA
1.52V     -30.88mA   -12.51mA   -49.05mA
2.56V     -32.88mA   -13.48mA   -52.9mA
3.28V     -34.18mA   -25.51mA   -54.17mA
3.6V      -41.3mA    -30.74mA   -54.97mA
4.32V     -62.46mA   -30.74mA   -77.8mA
4.72V     -62.46mA   -30.74mA   -93.1mA
[GND_clamp]
|Voltage   I(typ)   I(min)   I(max)
-2.4V     -1.425A    -1.508A    -1.394A
-1.25V    -311.2mA   -401.9mA   -273.3mA
-1.2V     -265.4mA   -356.1mA   -227.2mA
-1.15V    -220.4mA   -310.8mA   -181.9mA
-1.1V     -176.3mA   -266.2mA   -137.9mA
-1.05V    -133.8mA   -222.5mA   -95.87mA
-950mV    -57.3mA    -138.9mA   -26.98mA
-900mV    -28.27mA   -100.4mA   -10.59mA
-850mV    -11.01mA   -65.54mA   -5.958mA
-750mV    -2.834mA   -16.5mA    -3.178mA
-600mV    -750uA     -1.164mA   -738.3uA
2.35V     0A         0A         0A
[POWER_clamp]
|Voltage   I(typ)   I(min)   I(max)
-2.4V     447.7uA    170.8uA    719.3uA
-1.77V    447.7uA    170.8uA    719.3uA
-1.74V    447.7uA    170.8uA    707.6uA
-1.65V    447.7uA    170.8uA    647uA
-1.62V    442uA      170.8uA    625.5uA
-1.29V    280.9uA    170.8uA    395.1uA
-1.02V    161uA      101.5uA    230.1uA
-780mV    78.34uA    49.93uA    112.9uA
-600mV    36.03uA    23.94uA    50.74uA
-450mV    15.19uA    11.76uA    19.45uA
-330mV    8.429uA    7.427uA    9.749uA
0V        0A         0A         0A
[Ramp]
| variable   typ   min   max
dV/dt_r  0.82201/30.92809n   0.36328/83.89087n   1.11083/14.57471n
dV/dt_f  0.83682/29.99769n   0.32652/82.27500n   1.13668/15.80973n
R_load = 50.000000
[Rising Waveform]
R_fixture= 50.000000
V_fixture= 2.400000
V_fixture_min= 1.800000
V_fixture_max= 2.700000
|time   V(typ)   V(min)   V(max)
0s        1.007V     1.247V     805.7mV
780.8ps   1.013V     1.247V     848mV
880.9ps   1.017V     1.247V     998.7mV
1.161ns   1.096V     1.247V     2.471V
1.401ns   1.517V     1.247V     2.68V
1.562ns   2.059V     1.255V     2.694V
1.722ns   2.345V     1.263V     2.697V
1.862ns   2.39V      1.27V      2.698V
3.463ns   2.4V       1.804V     2.7V
9.97ns    2.4V       1.8V       2.7V
[Rising Waveform]
R_fixture= 50.000000
V_fixture= 0.0
V_fixture_min= 0.0
V_fixture_max= 0.0
|time   V(typ)   V(min)   V(max)
0s        880.4uV    840.2uV    911.2uV
6.507ns   3.857mV    1.889mV    48.62mV
17.02ns   101.4mV    2.044mV    746.9mV
28.03ns   380.2mV    8.665mV    1.549V
34.53ns   560.7mV    15.38mV    1.717V
42.54ns   791.8mV    42.88mV    1.792V
59.56ns   1.174V     101.3mV    1.839V
79.58ns   1.316V     194.6mV    1.848V
153.2ns   1.369V     512mV      1.852V
249.2ns   1.371V     610.3mV    1.852V
[Falling Waveform]
R_fixture= 50.000000
V_fixture= 2.400000
V_fixture_min= 1.800000
V_fixture_max= 2.700000
|time   V(typ)   V(min)   V(max)
0s        2.4V       1.8V       2.7V
8.509ns   2.4V       1.8V       2.681V
13.01ns   2.394V     1.8V       2.51V
24.02ns   2.25V      1.8V       1.687V
32.03ns   2.001V     1.795V     1.153V
43.04ns   1.68V      1.777V     917.9mV
60.06ns   1.24V      1.719V     847.9mV
85.09ns   1.08V      1.581V     819.2mV
158.2ns   1.015V     1.323V     805.8mV
249.2ns   1.007V     1.247V     805.7mV
[Falling Waveform]
R_fixture= 50.000000
V_fixture= 0.0
V_fixture_min= 0.0
V_fixture_max= 0.0
|time   V(typ)   V(min)   V(max)
0s        1.371V     610.3mV    1.852V
900.9ps   1.372V     610.1mV    1.791V
1.101ns   1.368V     610mV      1.399V
1.481ns   1.147V     609.7mV    310.7mV
1.862ns   522.5mV    610.6mV    28.49mV
2.242ns   107.2mV    607.7mV    4.686mV
2.643ns   13.27mV    567.2mV    1.704mV
3.584ns   1.374mV    201.1mV    1.105mV
4.805ns   909.7uV    8.966mV    1.086mV
9.97ns    880.4uV    840.2uV    911.2uV
